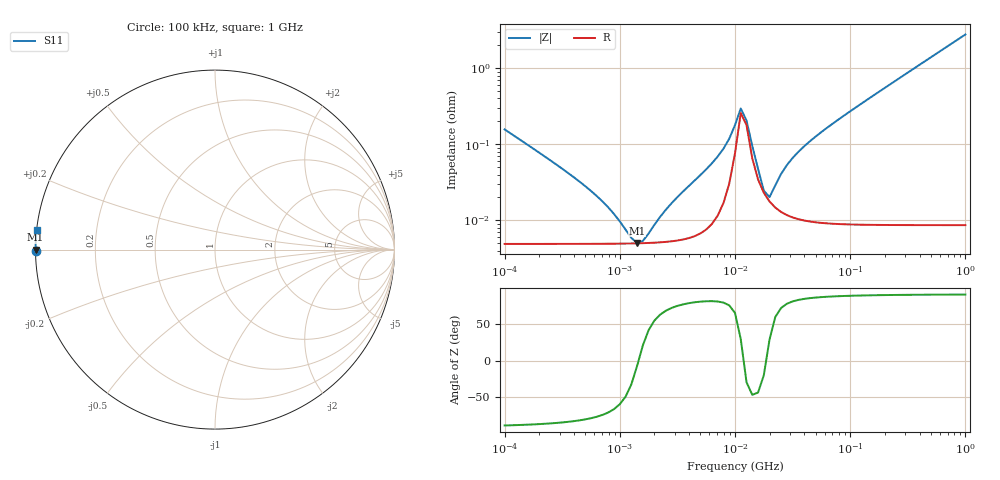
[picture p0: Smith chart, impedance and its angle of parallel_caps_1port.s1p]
# Hz S RI R 50
! golden: parallel_caps_1port
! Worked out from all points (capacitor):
!   81 points, 100 kHz to 1 GHz, reference 50 ohm
!   read as one part to ground: C = 10.1 uF near 100 kHz
!   lowest |Z| = 5.03 mohm at 1.413 MHz (marker M1)
!   series resonance near 1.456 MHz, so ESL is about 1.2 nH
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100000  -0.9998 -0.00627
177827.9  -0.9998 -0.00349
354813.4  -0.9998 -0.00167
1000000  -0.9998 -0.000334
1412538  -0.9998 -2.55e-05
3548134  -0.9998 0.000935
7079458  -0.9995 0.00272
8912509  -0.9988 0.00457
1e7  -0.9969 0.00646
1.122018e7  -0.9897 0.00571
1.258925e7  -0.9929 -0.00401
1.412538e7  -0.9974 -0.00276
1.584893e7  -0.9986 -0.00131
1.995262e7  -0.9993 0.00039
3.548134e7  -0.9996 0.00316
7.079458e7  -0.9996 0.0075
1.122018e8  -0.9996 0.0122
1.584893e8  -0.9995 0.0174
1.995262e8  -0.9994 0.022
2.818383e8  -0.9992 0.0312
3.548134e8  -0.9989 0.0393
4.466836e8  -0.9984 0.0495
5.011872e8  -0.9981 0.0556
6.309573e8  -0.9972 0.07
7.079458e8  -0.9966 0.0785
7.943282e8  -0.9958 0.088
8.912509e8  -0.9948 0.0987
1e9  -0.9935 0.1107
